VERSION 5.7 ;
  NOWIREEXTENSIONATPIN ON ;
  DIVIDERCHAR "/" ;
  BUSBITCHARS "[]" ;
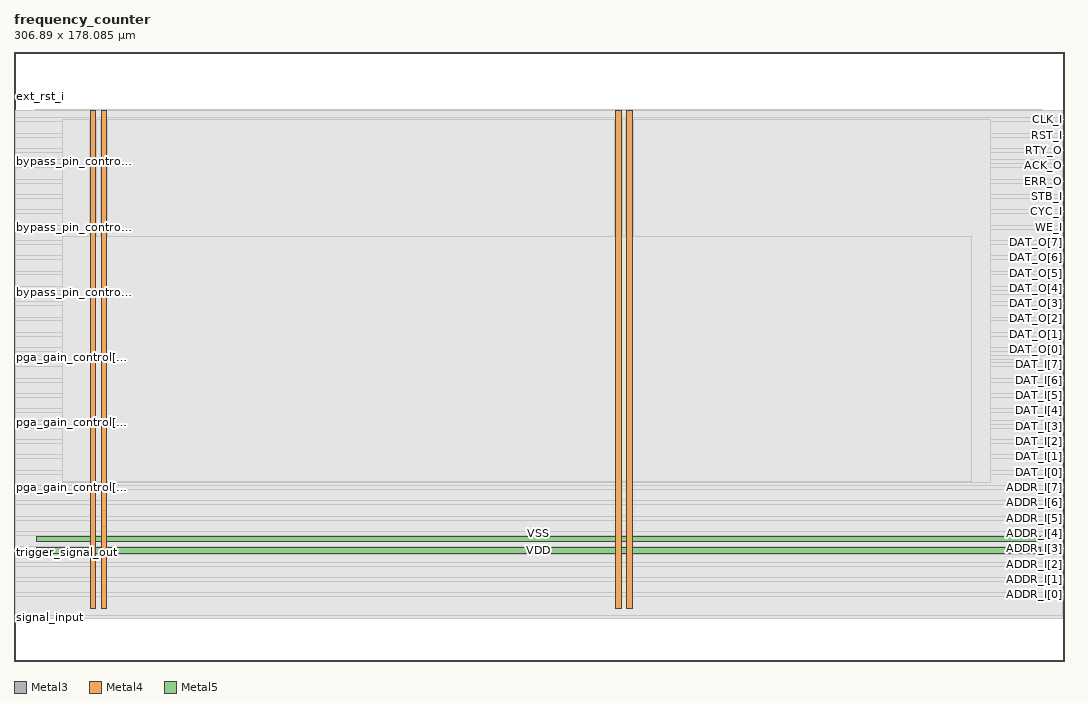
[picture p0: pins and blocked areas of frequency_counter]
MACRO frequency_counter
  CLASS BLOCK ;
  FOREIGN frequency_counter ;
  ORIGIN 0.000 0.000 ;
  SIZE 306.890 BY 178.085 ;
  PIN ACK_O
    DIRECTION OUTPUT ;
    USE SIGNAL ;
    ANTENNADIFFAREA 0.897600 ;
    PORT
      LAYER Metal3 ;
        RECT 306.330 144.480 306.890 145.040 ;
    END
  END ACK_O
  PIN ADDR_I[0]
    DIRECTION INPUT ;
    USE SIGNAL ;
    ANTENNAGATEAREA 0.396000 ;
    PORT
      LAYER Metal3 ;
        RECT 306.330 19.040 306.890 19.600 ;
    END
  END ADDR_I[0]
  PIN ADDR_I[1]
    DIRECTION INPUT ;
    USE SIGNAL ;
    ANTENNAGATEAREA 0.396000 ;
    PORT
      LAYER Metal3 ;
        RECT 306.330 23.520 306.890 24.080 ;
    END
  END ADDR_I[1]
  PIN ADDR_I[2]
    DIRECTION INPUT ;
    USE SIGNAL ;
    ANTENNAGATEAREA 0.396000 ;
    PORT
      LAYER Metal3 ;
        RECT 306.330 28.000 306.890 28.560 ;
    END
  END ADDR_I[2]
  PIN ADDR_I[3]
    DIRECTION INPUT ;
    USE SIGNAL ;
    ANTENNAGATEAREA 0.396000 ;
    PORT
      LAYER Metal3 ;
        RECT 306.330 32.480 306.890 33.040 ;
    END
  END ADDR_I[3]
  PIN ADDR_I[4]
    DIRECTION INPUT ;
    USE SIGNAL ;
    ANTENNAGATEAREA 0.396000 ;
    PORT
      LAYER Metal3 ;
        RECT 306.330 36.960 306.890 37.520 ;
    END
  END ADDR_I[4]
  PIN ADDR_I[5]
    DIRECTION INPUT ;
    USE SIGNAL ;
    ANTENNAGATEAREA 0.396000 ;
    PORT
      LAYER Metal3 ;
        RECT 306.330 41.440 306.890 42.000 ;
    END
  END ADDR_I[5]
  PIN ADDR_I[6]
    DIRECTION INPUT ;
    USE SIGNAL ;
    ANTENNAGATEAREA 0.396000 ;
    PORT
      LAYER Metal3 ;
        RECT 306.330 45.920 306.890 46.480 ;
    END
  END ADDR_I[6]
  PIN ADDR_I[7]
    DIRECTION INPUT ;
    USE SIGNAL ;
    ANTENNAGATEAREA 0.396000 ;
    PORT
      LAYER Metal3 ;
        RECT 306.330 50.400 306.890 50.960 ;
    END
  END ADDR_I[7]
  PIN CLK_I
    DIRECTION INPUT ;
    USE SIGNAL ;
    ANTENNAGATEAREA 4.738000 ;
    PORT
      LAYER Metal3 ;
        RECT 306.330 157.920 306.890 158.480 ;
    END
  END CLK_I
  PIN CYC_I
    DIRECTION INPUT ;
    USE SIGNAL ;
    ANTENNAGATEAREA 0.396000 ;
    PORT
      LAYER Metal3 ;
        RECT 306.330 131.040 306.890 131.600 ;
    END
  END CYC_I
  PIN DAT_I[0]
    DIRECTION INPUT ;
    USE SIGNAL ;
    ANTENNAGATEAREA 0.396000 ;
    PORT
      LAYER Metal3 ;
        RECT 306.330 54.880 306.890 55.440 ;
    END
  END DAT_I[0]
  PIN DAT_I[1]
    DIRECTION INPUT ;
    USE SIGNAL ;
    ANTENNAGATEAREA 0.396000 ;
    PORT
      LAYER Metal3 ;
        RECT 306.330 59.360 306.890 59.920 ;
    END
  END DAT_I[1]
  PIN DAT_I[2]
    DIRECTION INPUT ;
    USE SIGNAL ;
    ANTENNAGATEAREA 0.396000 ;
    PORT
      LAYER Metal3 ;
        RECT 306.330 63.840 306.890 64.400 ;
    END
  END DAT_I[2]
  PIN DAT_I[3]
    DIRECTION INPUT ;
    USE SIGNAL ;
    ANTENNAGATEAREA 0.396000 ;
    PORT
      LAYER Metal3 ;
        RECT 306.330 68.320 306.890 68.880 ;
    END
  END DAT_I[3]
  PIN DAT_I[4]
    DIRECTION INPUT ;
    USE SIGNAL ;
    ANTENNAGATEAREA 0.396000 ;
    PORT
      LAYER Metal3 ;
        RECT 306.330 72.800 306.890 73.360 ;
    END
  END DAT_I[4]
  PIN DAT_I[5]
    DIRECTION INPUT ;
    USE SIGNAL ;
    ANTENNAGATEAREA 0.396000 ;
    PORT
      LAYER Metal3 ;
        RECT 306.330 77.280 306.890 77.840 ;
    END
  END DAT_I[5]
  PIN DAT_I[6]
    DIRECTION INPUT ;
    USE SIGNAL ;
    ANTENNAGATEAREA 0.396000 ;
    PORT
      LAYER Metal3 ;
        RECT 306.330 81.760 306.890 82.320 ;
    END
  END DAT_I[6]
  PIN DAT_I[7]
    DIRECTION INPUT ;
    USE SIGNAL ;
    ANTENNAGATEAREA 0.396000 ;
    PORT
      LAYER Metal3 ;
        RECT 306.330 86.240 306.890 86.800 ;
    END
  END DAT_I[7]
  PIN DAT_O[0]
    DIRECTION OUTPUT ;
    USE SIGNAL ;
    ANTENNADIFFAREA 0.897600 ;
    PORT
      LAYER Metal3 ;
        RECT 306.330 90.720 306.890 91.280 ;
    END
  END DAT_O[0]
  PIN DAT_O[1]
    DIRECTION OUTPUT ;
    USE SIGNAL ;
    ANTENNADIFFAREA 0.897600 ;
    PORT
      LAYER Metal3 ;
        RECT 306.330 95.200 306.890 95.760 ;
    END
  END DAT_O[1]
  PIN DAT_O[2]
    DIRECTION OUTPUT ;
    USE SIGNAL ;
    ANTENNADIFFAREA 0.897600 ;
    PORT
      LAYER Metal3 ;
        RECT 306.330 99.680 306.890 100.240 ;
    END
  END DAT_O[2]
  PIN DAT_O[3]
    DIRECTION OUTPUT ;
    USE SIGNAL ;
    ANTENNADIFFAREA 0.897600 ;
    PORT
      LAYER Metal3 ;
        RECT 306.330 104.160 306.890 104.720 ;
    END
  END DAT_O[3]
  PIN DAT_O[4]
    DIRECTION OUTPUT ;
    USE SIGNAL ;
    ANTENNADIFFAREA 0.897600 ;
    PORT
      LAYER Metal3 ;
        RECT 306.330 108.640 306.890 109.200 ;
    END
  END DAT_O[4]
  PIN DAT_O[5]
    DIRECTION OUTPUT ;
    USE SIGNAL ;
    ANTENNADIFFAREA 0.897600 ;
    PORT
      LAYER Metal3 ;
        RECT 306.330 113.120 306.890 113.680 ;
    END
  END DAT_O[5]
  PIN DAT_O[6]
    DIRECTION OUTPUT ;
    USE SIGNAL ;
    ANTENNADIFFAREA 0.897600 ;
    PORT
      LAYER Metal3 ;
        RECT 306.330 117.600 306.890 118.160 ;
    END
  END DAT_O[6]
  PIN DAT_O[7]
    DIRECTION OUTPUT ;
    USE SIGNAL ;
    ANTENNADIFFAREA 0.897600 ;
    PORT
      LAYER Metal3 ;
        RECT 306.330 122.080 306.890 122.640 ;
    END
  END DAT_O[7]
  PIN ERR_O
    DIRECTION OUTPUT ;
    USE SIGNAL ;
    ANTENNADIFFAREA 0.897600 ;
    PORT
      LAYER Metal3 ;
        RECT 306.330 140.000 306.890 140.560 ;
    END
  END ERR_O
  PIN RST_I
    DIRECTION INPUT ;
    USE SIGNAL ;
    ANTENNAGATEAREA 0.498500 ;
    PORT
      LAYER Metal3 ;
        RECT 306.330 153.440 306.890 154.000 ;
    END
  END RST_I
  PIN RTY_O
    DIRECTION OUTPUT ;
    USE SIGNAL ;
    ANTENNADIFFAREA 0.360800 ;
    PORT
      LAYER Metal3 ;
        RECT 306.330 148.960 306.890 149.520 ;
    END
  END RTY_O
  PIN STB_I
    DIRECTION INPUT ;
    USE SIGNAL ;
    ANTENNAGATEAREA 0.396000 ;
    PORT
      LAYER Metal3 ;
        RECT 306.330 135.520 306.890 136.080 ;
    END
  END STB_I
  PIN VDD
    DIRECTION INOUT ;
    USE POWER ;
    PORT
      LAYER Metal4 ;
        RECT 22.240 15.380 23.840 161.020 ;
    END
    PORT
      LAYER Metal4 ;
        RECT 175.840 15.380 177.440 161.020 ;
    END
    PORT
      LAYER Metal5 ;
        RECT 6.720 31.530 300.160 33.130 ;
    END
  END VDD
  PIN VSS
    DIRECTION INOUT ;
    USE GROUND ;
    PORT
      LAYER Metal4 ;
        RECT 25.540 15.380 27.140 161.020 ;
    END
    PORT
      LAYER Metal4 ;
        RECT 179.140 15.380 180.740 161.020 ;
    END
    PORT
      LAYER Metal5 ;
        RECT 6.720 34.830 300.160 36.430 ;
    END
  END VSS
  PIN WE_I
    DIRECTION INPUT ;
    USE SIGNAL ;
    ANTENNAGATEAREA 0.396000 ;
    PORT
      LAYER Metal3 ;
        RECT 306.330 126.560 306.890 127.120 ;
    END
  END WE_I
  PIN bypass_pin_control[0]
    DIRECTION OUTPUT ;
    USE SIGNAL ;
    ANTENNADIFFAREA 0.897600 ;
    PORT
      LAYER Metal3 ;
        RECT 0.000 107.520 0.560 108.080 ;
    END
  END bypass_pin_control[0]
  PIN bypass_pin_control[1]
    DIRECTION OUTPUT ;
    USE SIGNAL ;
    ANTENNADIFFAREA 0.897600 ;
    PORT
      LAYER Metal3 ;
        RECT 0.000 126.560 0.560 127.120 ;
    END
  END bypass_pin_control[1]
  PIN bypass_pin_control[2]
    DIRECTION OUTPUT ;
    USE SIGNAL ;
    ANTENNADIFFAREA 0.897600 ;
    PORT
      LAYER Metal3 ;
        RECT 0.000 145.600 0.560 146.160 ;
    END
  END bypass_pin_control[2]
  PIN ext_rst_i
    DIRECTION INPUT ;
    USE SIGNAL ;
    PORT
      LAYER Metal3 ;
        RECT 0.000 164.640 0.560 165.200 ;
    END
  END ext_rst_i
  PIN pga_gain_control[0]
    DIRECTION OUTPUT ;
    USE SIGNAL ;
    ANTENNADIFFAREA 0.897600 ;
    PORT
      LAYER Metal3 ;
        RECT 0.000 50.400 0.560 50.960 ;
    END
  END pga_gain_control[0]
  PIN pga_gain_control[1]
    DIRECTION OUTPUT ;
    USE SIGNAL ;
    ANTENNADIFFAREA 0.897600 ;
    PORT
      LAYER Metal3 ;
        RECT 0.000 69.440 0.560 70.000 ;
    END
  END pga_gain_control[1]
  PIN pga_gain_control[2]
    DIRECTION OUTPUT ;
    USE SIGNAL ;
    ANTENNADIFFAREA 0.897600 ;
    PORT
      LAYER Metal3 ;
        RECT 0.000 88.480 0.560 89.040 ;
    END
  END pga_gain_control[2]
  PIN signal_input
    DIRECTION INPUT ;
    USE SIGNAL ;
    ANTENNAGATEAREA 9.476000 ;
    PORT
      LAYER Metal3 ;
        RECT 0.000 12.320 0.560 12.880 ;
    END
  END signal_input
  PIN trigger_signal_out
    DIRECTION OUTPUT ;
    USE SIGNAL ;
    ANTENNADIFFAREA 0.897600 ;
    PORT
      LAYER Metal3 ;
        RECT 0.000 31.360 0.560 31.920 ;
    END
  END trigger_signal_out
  OBS
      LAYER Nwell ;
        RECT 6.290 15.250 300.590 161.150 ;
      LAYER Metal1 ;
        RECT 6.720 15.380 300.160 161.020 ;
      LAYER Metal2 ;
        RECT 7.980 12.410 300.020 160.910 ;
      LAYER Metal3 ;
        RECT 0.560 158.780 306.330 160.860 ;
        RECT 0.560 157.620 306.030 158.780 ;
        RECT 0.560 154.300 306.330 157.620 ;
        RECT 0.560 153.140 306.030 154.300 ;
        RECT 0.560 149.820 306.330 153.140 ;
        RECT 0.560 148.660 306.030 149.820 ;
        RECT 0.560 146.460 306.330 148.660 ;
        RECT 0.860 145.340 306.330 146.460 ;
        RECT 0.860 145.300 306.030 145.340 ;
        RECT 0.560 144.180 306.030 145.300 ;
        RECT 0.560 140.860 306.330 144.180 ;
        RECT 0.560 139.700 306.030 140.860 ;
        RECT 0.560 136.380 306.330 139.700 ;
        RECT 0.560 135.220 306.030 136.380 ;
        RECT 0.560 131.900 306.330 135.220 ;
        RECT 0.560 130.740 306.030 131.900 ;
        RECT 0.560 127.420 306.330 130.740 ;
        RECT 0.860 126.260 306.030 127.420 ;
        RECT 0.560 122.940 306.330 126.260 ;
        RECT 0.560 121.780 306.030 122.940 ;
        RECT 0.560 118.460 306.330 121.780 ;
        RECT 0.560 117.300 306.030 118.460 ;
        RECT 0.560 113.980 306.330 117.300 ;
        RECT 0.560 112.820 306.030 113.980 ;
        RECT 0.560 109.500 306.330 112.820 ;
        RECT 0.560 108.380 306.030 109.500 ;
        RECT 0.860 108.340 306.030 108.380 ;
        RECT 0.860 107.220 306.330 108.340 ;
        RECT 0.560 105.020 306.330 107.220 ;
        RECT 0.560 103.860 306.030 105.020 ;
        RECT 0.560 100.540 306.330 103.860 ;
        RECT 0.560 99.380 306.030 100.540 ;
        RECT 0.560 96.060 306.330 99.380 ;
        RECT 0.560 94.900 306.030 96.060 ;
        RECT 0.560 91.580 306.330 94.900 ;
        RECT 0.560 90.420 306.030 91.580 ;
        RECT 0.560 89.340 306.330 90.420 ;
        RECT 0.860 88.180 306.330 89.340 ;
        RECT 0.560 87.100 306.330 88.180 ;
        RECT 0.560 85.940 306.030 87.100 ;
        RECT 0.560 82.620 306.330 85.940 ;
        RECT 0.560 81.460 306.030 82.620 ;
        RECT 0.560 78.140 306.330 81.460 ;
        RECT 0.560 76.980 306.030 78.140 ;
        RECT 0.560 73.660 306.330 76.980 ;
        RECT 0.560 72.500 306.030 73.660 ;
        RECT 0.560 70.300 306.330 72.500 ;
        RECT 0.860 69.180 306.330 70.300 ;
        RECT 0.860 69.140 306.030 69.180 ;
        RECT 0.560 68.020 306.030 69.140 ;
        RECT 0.560 64.700 306.330 68.020 ;
        RECT 0.560 63.540 306.030 64.700 ;
        RECT 0.560 60.220 306.330 63.540 ;
        RECT 0.560 59.060 306.030 60.220 ;
        RECT 0.560 55.740 306.330 59.060 ;
        RECT 0.560 54.580 306.030 55.740 ;
        RECT 0.560 51.260 306.330 54.580 ;
        RECT 0.860 50.100 306.030 51.260 ;
        RECT 0.560 46.780 306.330 50.100 ;
        RECT 0.560 45.620 306.030 46.780 ;
        RECT 0.560 42.300 306.330 45.620 ;
        RECT 0.560 41.140 306.030 42.300 ;
        RECT 0.560 37.820 306.330 41.140 ;
        RECT 0.560 36.660 306.030 37.820 ;
        RECT 0.560 33.340 306.330 36.660 ;
        RECT 0.560 32.220 306.030 33.340 ;
        RECT 0.860 32.180 306.030 32.220 ;
        RECT 0.860 31.060 306.330 32.180 ;
        RECT 0.560 28.860 306.330 31.060 ;
        RECT 0.560 27.700 306.030 28.860 ;
        RECT 0.560 24.380 306.330 27.700 ;
        RECT 0.560 23.220 306.030 24.380 ;
        RECT 0.560 19.900 306.330 23.220 ;
        RECT 0.560 18.740 306.030 19.900 ;
        RECT 0.560 13.180 306.330 18.740 ;
        RECT 0.860 12.460 306.330 13.180 ;
      LAYER Metal4 ;
        RECT 14.140 52.170 21.940 158.390 ;
        RECT 24.140 52.170 25.240 158.390 ;
        RECT 27.440 52.170 175.540 158.390 ;
        RECT 177.740 52.170 178.840 158.390 ;
        RECT 181.040 52.170 285.460 158.390 ;
      LAYER Metal5 ;
        RECT 14.060 52.430 279.940 123.970 ;
  END
END frequency_counter
END LIBRARY

